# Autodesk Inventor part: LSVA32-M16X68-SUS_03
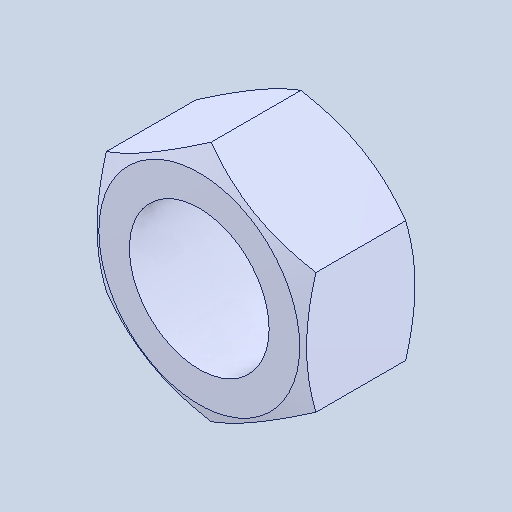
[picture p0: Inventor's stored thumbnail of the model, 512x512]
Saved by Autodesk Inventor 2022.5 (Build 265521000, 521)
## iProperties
Created: 2024-08
Part Number: LSVA32-M16X68-SUS_03
Material: 一般
Document SubType Name: Modeling
Designer: ImaoCorp
Density: 1 g/cm^3
Appearance: 既定
Author: ImaoCorp
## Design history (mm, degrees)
feature "LSVA32-M16X68-SUS_03"
node "ソリッド1"
